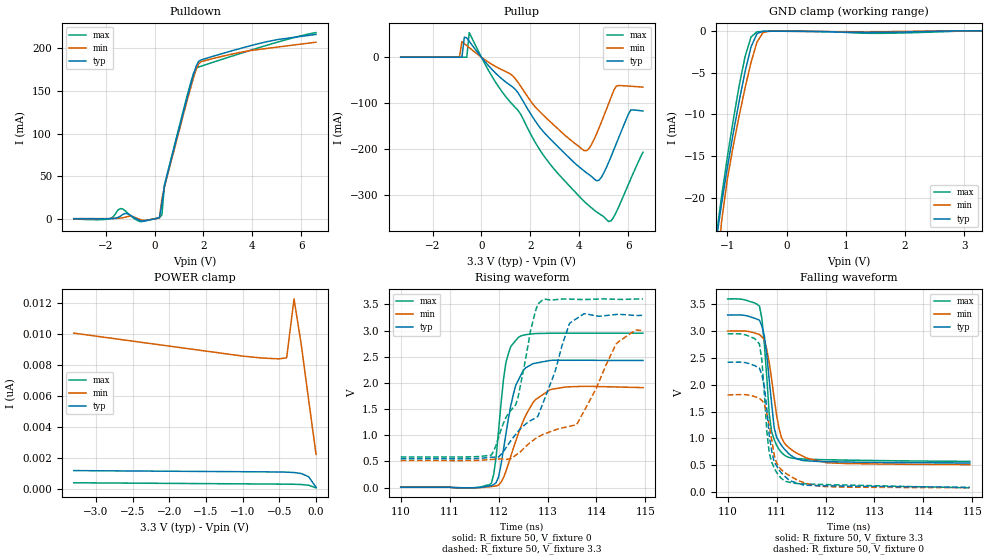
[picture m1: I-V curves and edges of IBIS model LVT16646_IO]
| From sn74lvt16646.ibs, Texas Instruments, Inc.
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|   Model LVT16646  I/O
[Model]   LVT16646_IO
| Signals
Model_type  I/O
Polarity   Inverting
Enable   Active-Low
Vinl = 0.8V
Vinh = 2.0V
Vmeas= 1.5V
Cref = 50pF
Rref = 500
Vref = 0V
| variable   typ   min   max
C_comp   10p   NA   NA
[Temperature Range]   50   100   0
[Voltage range]   3.3   3   3.6
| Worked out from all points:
|   slope of the pulldown table from 0 to 0.495 V, typ, clamps not added: 10.1 ohm
|   slope of the pullup table from 0 to 0.495 V, typ, clamps not added: 16.5 ohm
|   GND clamp passes 1 mA (typ) near -0.54 V on its own axis
|   rising waveform, R_fixture 50, V_fixture 0: 20-80 % time 289ps typ, 468ps min, 195ps max; typ from 0.008 V to 2.43 V
|   falling waveform, R_fixture 50, V_fixture 3.3: 20-80 % time 208ps typ, 274ps min, 167ps max; typ from 3.3 V to 0.54 V
|   rising waveform, R_fixture 50, V_fixture 3.3: 20-80 % time 885ps typ, 1.38ns min, 572ps max; typ from 0.55 V to 3.29 V
|   falling waveform, R_fixture 50, V_fixture 0: 20-80 % time 203ps typ, 288ps min, 165ps max; typ from 2.42 V to 0.086 V
|Process range|   weak   strong
[Pullup]
|   50C:3.3V:   100C:3V:weak   0C:3.6V:strong
|   Voltage   I(typ)   I(min)   I(max)
-3.3V     70.42uA    59uA       80.74uA
-900mV    69.34uA    46.3uA     79.72uA
-800mV    63.3uA     34.29mA    79.65uA
-600mV    42.05mA    25.32mA    54.26uA
-500mV    34.8mA     20.93mA    53.67mA
2.5V      -159.8mA   -124.4mA   -210.4mA
4.2V      -247.2mA   -202.8mA   -313.4mA
4.8V      -267.2mA   -154.2mA   -339.6mA
5.2V      -227.9mA   -100.2mA   -357mA
5.5V      -188.9mA   -63.05mA   -337.4mA
6.1V      -114.5mA   -62.95mA   -264.3mA
6.6V      -116.7mA   -64.77mA   -206.2mA
[Pulldown]
|   50C:3.3V:   100C:3V:weak   0C:3.6V:strong
|   Voltage   I(typ)   I(min)   I(max)
-3.3V     -9.3uA     -5.2uA     -453.5uA
-1.9V     -193.8uA   131.5uA    -406.1uA
-1.4V     2.844mA    670.9uA    11.85mA
-1.1V     5.759mA    2.496mA    6.461mA
-600mV    -2.184mA   -906.9uA   -3.383mA
200mV     1.166mA    1.173mA    1.18mA
300mV     17.85mA    23.06mA    4.35mA
400mV     37.77mA    36.59mA    38.76mA
1.3V      138.4mA    135.3mA    140.8mA
1.6V      170mA      166.3mA    171.2mA
1.8V      184.7mA    181.8mA    178.1mA
6.6V      216.4mA    207.3mA    218.6mA
[GND Clamp]
|   50C:3.3V:   100C:3V:weak   0C:3.6V:strong
|   Voltage   I(typ)   I(min)   I(max)
-3.3V     -676.2mA   -692.6mA   -650.2mA
-1.2V     -25.72mA   -32.64mA   -25.32mA
-1.1V     -20.85mA   -23mA      -19.98mA
-1V       -16.39mA   -17.76mA   -15.12mA
-800mV    -8.401mA   -10.17mA   -6.567mA
-700mV    -4.863mA   -6.812mA   -3.059mA
-600mV    -1.917mA   -3.774mA   -735.8uA
-500mV    -337.2uA   -1.357mA   -110.9uA
-400mV    -58.38uA   -218.7uA   -69.9uA
-300mV    -43.11uA   -52.96uA   -53.94uA
1.5V      -188.1uA   -101uA     -299.2uA
3.3V      87.94pA    12.28nA    -2.772nA
[POWER Clamp]
|   50C:3.3V:   100C:3V:weak   0C:3.6V:strong
|   Voltage   I(typ)   I(min)   I(max)
-3.3V     1.168nA    10.06nA    380.5pA
-1V       1.096nA    8.576nA    310.4pA
-500mV    1.078nA    8.398nA    294.3pA
-400mV    1.069nA    8.47nA     290.2pA
-300mV    1.045nA    12.28nA    283.8pA
-200mV    977.4pA    9.267nA    268.4pA
-100mV    768.5pA    5.709nA    220.4pA
0V        87.94pA    2.215nA    52.35pA
[ramp]
| variable   typ   min   max
dV/dt_r   1.9218E+00/2.3821E-10  1.7128E+00/4.0695E-10  2.1214E+00/1.5990E-10
dV/dt_f   1.6628E+00/2.0949E-10  1.5034E+00/2.7594E-10  1.8220E+00/1.5759E-10
[Rising Waveform]
R_fixture = 50
V_fixture = 0
V_fixture_min=0
V_fixture_max=0
C_fixture= 0pF
L_fixture= 0n
|   50C:3.3V:   100C:3V:weak   0C:3.6V:strong
|   Time   V(typ)   V(min)   V(max)
110ns     8.015mV    7.523mV    7.107mV
111.8ns   35.2mV     18.82mV    78.15mV
112ns     94.41mV    32.58mV    588.9mV
112ns     205.1mV    47.54mV    1.093V
112.1ns   1.028V     312.6mV    2.391V
112.3ns   1.775V     747.4mV    2.753V
112.4ns   2.045V     1.024V     2.866V
112.7ns   2.366V     1.618V     2.938V
113ns     2.428V     1.87V      2.948V
114.9ns   2.428V     1.91V      2.95V
[Falling Waveform]
R_fixture = 50
V_fixture = 3.3
V_fixture_min = 3
V_fixture_max = 3.6
C_fixture= 0pF
L_fixture= 0n
|   50C:3.3V:   100C:3V:weak   0C:3.6V:strong
|   Time   V(typ)   V(min)   V(max)
110ns     3.3V       3V         3.6V
110.7ns   3.205V     2.937V     3.467V
110.7ns   2.91V      2.841V     2.756V
110.9ns   2.088V     2.414V     1.455V
110.9ns   1.638V     2.097V     1.121V
111ns     1.021V     1.433V     871mV
111.1ns   868mV      1.017V     736mV
111.2ns   760mV      869mV      663mV
112.1ns   565mV      543mV      600mV
114.9ns   540mV      509mV      570mV
[Rising Waveform]
R_fixture = 50
V_fixture = 3.3
V_fixture_min = 3
V_fixture_max = 3.6
C_fixture= 0pF
L_fixture= 0n
|   50C:3.3V:   100C:3V:weak   0C:3.6V:strong
|   Time   V(typ)   V(min)   V(max)
110ns     550.5mV    516.1mV    585.5mV
111.8ns   580.8mV    537.2mV    618.9mV
112.1ns   759.7mV    539.1mV    1.339V
112.3ns   1.017V     618.8mV    1.584V
112.8ns   1.327V     935.1mV    3.362V
112.9ns   1.598V     1.014V     3.586V
113.5ns   3.137V     1.17V      3.601V
113.6ns   3.232V     1.21V      3.596V
114.4ns   3.307V     2.743V     3.598V
114.9ns   3.292V     2.998V     3.604V
[Falling Waveform]
R_fixture = 50
V_fixture = 0
V_fixture_min=0
V_fixture_max=0
C_fixture= 0pF
L_fixture= 0n
|   50C:3.3V:   100C:3V:weak   0C:3.6V:strong
|   Time   V(typ)   V(min)   V(max)
110ns     2.419V     1.809V     2.95V
110.7ns   2.309V     1.746V     2.758V
110.7ns   2.181V     1.703V     2.453V
110.7ns   1.966V     1.65V      1.841V
110.8ns   1.55V      1.467V     1.142V
110.9ns   1.051V     1.234V     722mV
111ns     488mV      537mV      365mV
111.1ns   305mV      374mV      216mV
111.9ns   117mV      104mV      140mV
114.9ns   86.1mV     79.8mV     76.4mV
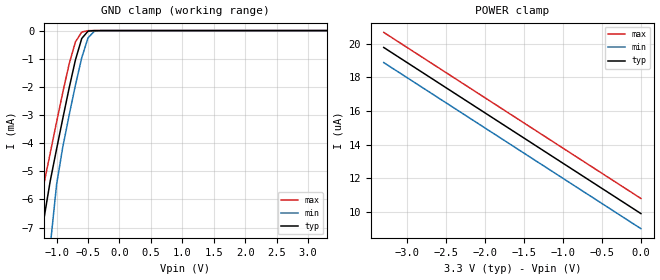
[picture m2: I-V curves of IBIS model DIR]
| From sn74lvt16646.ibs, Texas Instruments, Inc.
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|   LVT16646 DIR (DIR)
[Model]   DIR
| Signals
Model_type  Input
Polarity   Non-Inverting
Enable   Active-Low
Vinl = 0.8V
Vinh = 2.0V
| variable   typ   min   max
C_comp   4p   NA   NA
[Temperature Range]   50   100   0
[Voltage range]   3.3   3   3.6
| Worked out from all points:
|   GND clamp passes 1 mA (typ) near -0.69 V on its own axis
|Process range|   weak   strong
[GND Clamp]
|   50C:3.3V:   100C:3V:weak   0C:3.6V:strong
|   Voltage   I(typ)   I(min)   I(max)
-3.3V     -224.8mA   -241.1mA   -208.9mA
-1.4V     -13.34mA   -23.11mA   -7.939mA
-1.3V     -9.109mA   -16.37mA   -6.553mA
-1.2V     -6.671mA   -11.19mA   -5.438mA
-1.1V     -5.33mA    -7.633mA   -4.337mA
-1V       -4.207mA   -5.465mA   -3.247mA
-800mV    -2.038mA   -2.999mA   -1.182mA
-700mV    -1.04mA    -1.936mA   -400.5uA
-600mV    -281.5uA   -964.1uA   -52.43uA
-500mV    -20.18uA   -260.4uA   -2.595uA
-400mV    -780.6nA   -22.92uA   -122.2nA
3.3V      21.93pA    409.1pA    10.64pA
[POWER Clamp]
|   50C:3.3V:   100C:3V:weak   0C:3.6V:strong
|   Voltage   I(typ)   I(min)   I(max)
-3.3V     19.78uA    18.89uA    20.68uA
-700mV    11.99uA    11.09uA    12.89uA
-300mV    10.79uA    9.893uA    11.69uA
0V        9.892uA    8.993uA    10.79uA
